VERSION 5.8 ;
BUSBITCHARS "[]" ;
DIVIDERCHAR "/" ;
UNITS
    DATABASE MICRONS 1000 ;
END UNITS

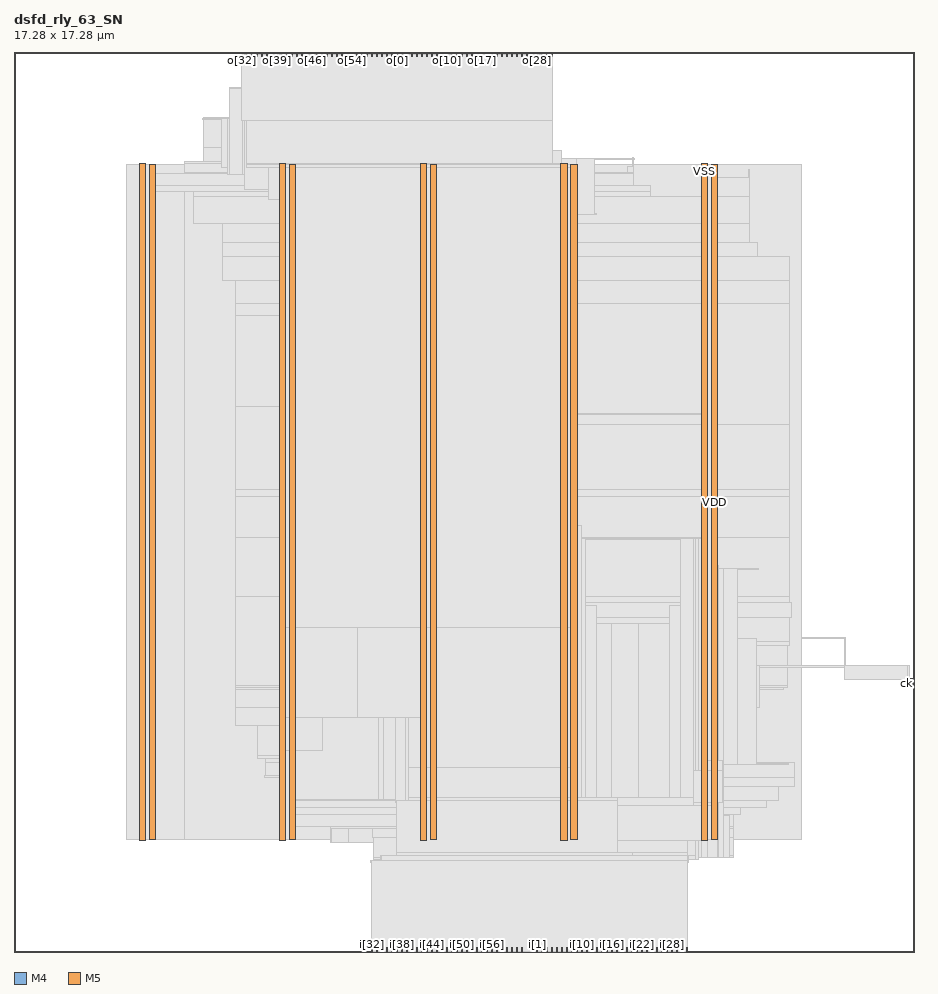
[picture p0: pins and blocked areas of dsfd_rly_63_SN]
MACRO dsfd_rly_63_SN
  FOREIGN dsfd_rly_63_SN 0 0 ;
  CLASS BLOCK ;
  SIZE 17.28 BY 17.28 ;
  PIN ck
    DIRECTION INPUT ;
    USE SIGNAL ;
    PORT
      LAYER M4 ;
        RECT  17.196 5.136 17.28 5.16 ;
    END
  END ck
  PIN i[0]
    DIRECTION INPUT ;
    USE SIGNAL ;
    PORT
      LAYER M5 ;
        RECT  9.936 0 9.96 0.084 ;
    END
  END i[0]
  PIN i[10]
    DIRECTION INPUT ;
    USE SIGNAL ;
    PORT
      LAYER M5 ;
        RECT  10.896 0 10.92 0.084 ;
    END
  END i[10]
  PIN i[11]
    DIRECTION INPUT ;
    USE SIGNAL ;
    PORT
      LAYER M5 ;
        RECT  10.992 0 11.016 0.084 ;
    END
  END i[11]
  PIN i[12]
    DIRECTION INPUT ;
    USE SIGNAL ;
    PORT
      LAYER M5 ;
        RECT  11.088 0 11.112 0.084 ;
    END
  END i[12]
  PIN i[13]
    DIRECTION INPUT ;
    USE SIGNAL ;
    PORT
      LAYER M5 ;
        RECT  11.184 0 11.208 0.084 ;
    END
  END i[13]
  PIN i[14]
    DIRECTION INPUT ;
    USE SIGNAL ;
    PORT
      LAYER M5 ;
        RECT  11.28 0 11.304 0.084 ;
    END
  END i[14]
  PIN i[15]
    DIRECTION INPUT ;
    USE SIGNAL ;
    PORT
      LAYER M5 ;
        RECT  11.376 0 11.4 0.084 ;
    END
  END i[15]
  PIN i[16]
    DIRECTION INPUT ;
    USE SIGNAL ;
    PORT
      LAYER M5 ;
        RECT  11.472 0 11.496 0.084 ;
    END
  END i[16]
  PIN i[17]
    DIRECTION INPUT ;
    USE SIGNAL ;
    PORT
      LAYER M5 ;
        RECT  11.568 0 11.592 0.084 ;
    END
  END i[17]
  PIN i[18]
    DIRECTION INPUT ;
    USE SIGNAL ;
    PORT
      LAYER M5 ;
        RECT  11.664 0 11.688 0.084 ;
    END
  END i[18]
  PIN i[19]
    DIRECTION INPUT ;
    USE SIGNAL ;
    PORT
      LAYER M5 ;
        RECT  11.76 0 11.784 0.084 ;
    END
  END i[19]
  PIN i[1]
    DIRECTION INPUT ;
    USE SIGNAL ;
    PORT
      LAYER M5 ;
        RECT  10.032 0 10.056 0.084 ;
    END
  END i[1]
  PIN i[20]
    DIRECTION INPUT ;
    USE SIGNAL ;
    PORT
      LAYER M5 ;
        RECT  11.856 0 11.88 0.084 ;
    END
  END i[20]
  PIN i[21]
    DIRECTION INPUT ;
    USE SIGNAL ;
    PORT
      LAYER M5 ;
        RECT  11.952 0 11.976 0.084 ;
    END
  END i[21]
  PIN i[22]
    DIRECTION INPUT ;
    USE SIGNAL ;
    PORT
      LAYER M5 ;
        RECT  12.048 0 12.072 0.084 ;
    END
  END i[22]
  PIN i[23]
    DIRECTION INPUT ;
    USE SIGNAL ;
    PORT
      LAYER M5 ;
        RECT  12.144 0 12.168 0.084 ;
    END
  END i[23]
  PIN i[24]
    DIRECTION INPUT ;
    USE SIGNAL ;
    PORT
      LAYER M5 ;
        RECT  12.24 0 12.264 0.084 ;
    END
  END i[24]
  PIN i[25]
    DIRECTION INPUT ;
    USE SIGNAL ;
    PORT
      LAYER M5 ;
        RECT  12.336 0 12.36 0.084 ;
    END
  END i[25]
  PIN i[26]
    DIRECTION INPUT ;
    USE SIGNAL ;
    PORT
      LAYER M5 ;
        RECT  12.432 0 12.456 0.084 ;
    END
  END i[26]
  PIN i[27]
    DIRECTION INPUT ;
    USE SIGNAL ;
    PORT
      LAYER M5 ;
        RECT  12.528 0 12.552 0.084 ;
    END
  END i[27]
  PIN i[28]
    DIRECTION INPUT ;
    USE SIGNAL ;
    PORT
      LAYER M5 ;
        RECT  12.624 0 12.648 0.084 ;
    END
  END i[28]
  PIN i[29]
    DIRECTION INPUT ;
    USE SIGNAL ;
    PORT
      LAYER M5 ;
        RECT  12.72 0 12.744 0.084 ;
    END
  END i[29]
  PIN i[2]
    DIRECTION INPUT ;
    USE SIGNAL ;
    PORT
      LAYER M5 ;
        RECT  10.128 0 10.152 0.084 ;
    END
  END i[2]
  PIN i[30]
    DIRECTION INPUT ;
    USE SIGNAL ;
    PORT
      LAYER M5 ;
        RECT  12.816 0 12.84 0.084 ;
    END
  END i[30]
  PIN i[31]
    DIRECTION INPUT ;
    USE SIGNAL ;
    PORT
      LAYER M5 ;
        RECT  12.912 0 12.936 0.084 ;
    END
  END i[31]
  PIN i[32]
    DIRECTION INPUT ;
    USE SIGNAL ;
    PORT
      LAYER M5 ;
        RECT  6.864 0 6.888 0.084 ;
    END
  END i[32]
  PIN i[33]
    DIRECTION INPUT ;
    USE SIGNAL ;
    PORT
      LAYER M5 ;
        RECT  6.96 0 6.984 0.084 ;
    END
  END i[33]
  PIN i[34]
    DIRECTION INPUT ;
    USE SIGNAL ;
    PORT
      LAYER M5 ;
        RECT  7.056 0 7.08 0.084 ;
    END
  END i[34]
  PIN i[35]
    DIRECTION INPUT ;
    USE SIGNAL ;
    PORT
      LAYER M5 ;
        RECT  7.152 0 7.176 0.084 ;
    END
  END i[35]
  PIN i[36]
    DIRECTION INPUT ;
    USE SIGNAL ;
    PORT
      LAYER M5 ;
        RECT  7.248 0 7.272 0.084 ;
    END
  END i[36]
  PIN i[37]
    DIRECTION INPUT ;
    USE SIGNAL ;
    PORT
      LAYER M5 ;
        RECT  7.344 0 7.368 0.084 ;
    END
  END i[37]
  PIN i[38]
    DIRECTION INPUT ;
    USE SIGNAL ;
    PORT
      LAYER M5 ;
        RECT  7.44 0 7.464 0.084 ;
    END
  END i[38]
  PIN i[39]
    DIRECTION INPUT ;
    USE SIGNAL ;
    PORT
      LAYER M5 ;
        RECT  7.536 0 7.56 0.084 ;
    END
  END i[39]
  PIN i[3]
    DIRECTION INPUT ;
    USE SIGNAL ;
    PORT
      LAYER M5 ;
        RECT  10.224 0 10.248 0.084 ;
    END
  END i[3]
  PIN i[40]
    DIRECTION INPUT ;
    USE SIGNAL ;
    PORT
      LAYER M5 ;
        RECT  7.632 0 7.656 0.084 ;
    END
  END i[40]
  PIN i[41]
    DIRECTION INPUT ;
    USE SIGNAL ;
    PORT
      LAYER M5 ;
        RECT  7.728 0 7.752 0.084 ;
    END
  END i[41]
  PIN i[42]
    DIRECTION INPUT ;
    USE SIGNAL ;
    PORT
      LAYER M5 ;
        RECT  7.824 0 7.848 0.084 ;
    END
  END i[42]
  PIN i[43]
    DIRECTION INPUT ;
    USE SIGNAL ;
    PORT
      LAYER M5 ;
        RECT  7.92 0 7.944 0.084 ;
    END
  END i[43]
  PIN i[44]
    DIRECTION INPUT ;
    USE SIGNAL ;
    PORT
      LAYER M5 ;
        RECT  8.016 0 8.04 0.084 ;
    END
  END i[44]
  PIN i[45]
    DIRECTION INPUT ;
    USE SIGNAL ;
    PORT
      LAYER M5 ;
        RECT  8.112 0 8.136 0.084 ;
    END
  END i[45]
  PIN i[46]
    DIRECTION INPUT ;
    USE SIGNAL ;
    PORT
      LAYER M5 ;
        RECT  8.208 0 8.232 0.084 ;
    END
  END i[46]
  PIN i[47]
    DIRECTION INPUT ;
    USE SIGNAL ;
    PORT
      LAYER M5 ;
        RECT  8.304 0 8.328 0.084 ;
    END
  END i[47]
  PIN i[48]
    DIRECTION INPUT ;
    USE SIGNAL ;
    PORT
      LAYER M5 ;
        RECT  8.4 0 8.424 0.084 ;
    END
  END i[48]
  PIN i[49]
    DIRECTION INPUT ;
    USE SIGNAL ;
    PORT
      LAYER M5 ;
        RECT  8.496 0 8.52 0.084 ;
    END
  END i[49]
  PIN i[4]
    DIRECTION INPUT ;
    USE SIGNAL ;
    PORT
      LAYER M5 ;
        RECT  10.32 0 10.344 0.084 ;
    END
  END i[4]
  PIN i[50]
    DIRECTION INPUT ;
    USE SIGNAL ;
    PORT
      LAYER M5 ;
        RECT  8.592 0 8.616 0.084 ;
    END
  END i[50]
  PIN i[51]
    DIRECTION INPUT ;
    USE SIGNAL ;
    PORT
      LAYER M5 ;
        RECT  8.688 0 8.712 0.084 ;
    END
  END i[51]
  PIN i[52]
    DIRECTION INPUT ;
    USE SIGNAL ;
    PORT
      LAYER M5 ;
        RECT  8.784 0 8.808 0.084 ;
    END
  END i[52]
  PIN i[53]
    DIRECTION INPUT ;
    USE SIGNAL ;
    PORT
      LAYER M5 ;
        RECT  8.88 0 8.904 0.084 ;
    END
  END i[53]
  PIN i[54]
    DIRECTION INPUT ;
    USE SIGNAL ;
    PORT
      LAYER M5 ;
        RECT  8.976 0 9 0.084 ;
    END
  END i[54]
  PIN i[55]
    DIRECTION INPUT ;
    USE SIGNAL ;
    PORT
      LAYER M5 ;
        RECT  9.072 0 9.096 0.084 ;
    END
  END i[55]
  PIN i[56]
    DIRECTION INPUT ;
    USE SIGNAL ;
    PORT
      LAYER M5 ;
        RECT  9.168 0 9.192 0.084 ;
    END
  END i[56]
  PIN i[57]
    DIRECTION INPUT ;
    USE SIGNAL ;
    PORT
      LAYER M5 ;
        RECT  9.264 0 9.288 0.084 ;
    END
  END i[57]
  PIN i[58]
    DIRECTION INPUT ;
    USE SIGNAL ;
    PORT
      LAYER M5 ;
        RECT  9.36 0 9.384 0.084 ;
    END
  END i[58]
  PIN i[59]
    DIRECTION INPUT ;
    USE SIGNAL ;
    PORT
      LAYER M5 ;
        RECT  9.456 0 9.48 0.084 ;
    END
  END i[59]
  PIN i[5]
    DIRECTION INPUT ;
    USE SIGNAL ;
    PORT
      LAYER M5 ;
        RECT  10.416 0 10.44 0.084 ;
    END
  END i[5]
  PIN i[60]
    DIRECTION INPUT ;
    USE SIGNAL ;
    PORT
      LAYER M5 ;
        RECT  9.552 0 9.576 0.084 ;
    END
  END i[60]
  PIN i[61]
    DIRECTION INPUT ;
    USE SIGNAL ;
    PORT
      LAYER M5 ;
        RECT  9.648 0 9.672 0.084 ;
    END
  END i[61]
  PIN i[62]
    DIRECTION INPUT ;
    USE SIGNAL ;
    PORT
      LAYER M5 ;
        RECT  9.744 0 9.768 0.084 ;
    END
  END i[62]
  PIN i[6]
    DIRECTION INPUT ;
    USE SIGNAL ;
    PORT
      LAYER M5 ;
        RECT  10.512 0 10.536 0.084 ;
    END
  END i[6]
  PIN i[7]
    DIRECTION INPUT ;
    USE SIGNAL ;
    PORT
      LAYER M5 ;
        RECT  10.608 0 10.632 0.084 ;
    END
  END i[7]
  PIN i[8]
    DIRECTION INPUT ;
    USE SIGNAL ;
    PORT
      LAYER M5 ;
        RECT  10.704 0 10.728 0.084 ;
    END
  END i[8]
  PIN i[9]
    DIRECTION INPUT ;
    USE SIGNAL ;
    PORT
      LAYER M5 ;
        RECT  10.8 0 10.824 0.084 ;
    END
  END i[9]
  PIN o[0]
    DIRECTION OUTPUT ;
    USE SIGNAL ;
    PORT
      LAYER M5 ;
        RECT  7.344 17.196 7.368 17.28 ;
    END
  END o[0]
  PIN o[10]
    DIRECTION OUTPUT ;
    USE SIGNAL ;
    PORT
      LAYER M5 ;
        RECT  8.304 17.196 8.328 17.28 ;
    END
  END o[10]
  PIN o[11]
    DIRECTION OUTPUT ;
    USE SIGNAL ;
    PORT
      LAYER M5 ;
        RECT  8.4 17.196 8.424 17.28 ;
    END
  END o[11]
  PIN o[12]
    DIRECTION OUTPUT ;
    USE SIGNAL ;
    PORT
      LAYER M5 ;
        RECT  8.496 17.196 8.52 17.28 ;
    END
  END o[12]
  PIN o[13]
    DIRECTION OUTPUT ;
    USE SIGNAL ;
    PORT
      LAYER M5 ;
        RECT  8.592 17.196 8.616 17.28 ;
    END
  END o[13]
  PIN o[14]
    DIRECTION OUTPUT ;
    USE SIGNAL ;
    PORT
      LAYER M5 ;
        RECT  8.688 17.196 8.712 17.28 ;
    END
  END o[14]
  PIN o[15]
    DIRECTION OUTPUT ;
    USE SIGNAL ;
    PORT
      LAYER M5 ;
        RECT  8.784 17.196 8.808 17.28 ;
    END
  END o[15]
  PIN o[16]
    DIRECTION OUTPUT ;
    USE SIGNAL ;
    PORT
      LAYER M5 ;
        RECT  8.88 17.196 8.904 17.28 ;
    END
  END o[16]
  PIN o[17]
    DIRECTION OUTPUT ;
    USE SIGNAL ;
    PORT
      LAYER M5 ;
        RECT  8.976 17.196 9 17.28 ;
    END
  END o[17]
  PIN o[18]
    DIRECTION OUTPUT ;
    USE SIGNAL ;
    PORT
      LAYER M5 ;
        RECT  9.072 17.196 9.096 17.28 ;
    END
  END o[18]
  PIN o[19]
    DIRECTION OUTPUT ;
    USE SIGNAL ;
    PORT
      LAYER M5 ;
        RECT  9.168 17.196 9.192 17.28 ;
    END
  END o[19]
  PIN o[1]
    DIRECTION OUTPUT ;
    USE SIGNAL ;
    PORT
      LAYER M5 ;
        RECT  7.44 17.196 7.464 17.28 ;
    END
  END o[1]
  PIN o[20]
    DIRECTION OUTPUT ;
    USE SIGNAL ;
    PORT
      LAYER M5 ;
        RECT  9.264 17.196 9.288 17.28 ;
    END
  END o[20]
  PIN o[21]
    DIRECTION OUTPUT ;
    USE SIGNAL ;
    PORT
      LAYER M5 ;
        RECT  9.36 17.196 9.384 17.28 ;
    END
  END o[21]
  PIN o[22]
    DIRECTION OUTPUT ;
    USE SIGNAL ;
    PORT
      LAYER M5 ;
        RECT  9.456 17.196 9.48 17.28 ;
    END
  END o[22]
  PIN o[23]
    DIRECTION OUTPUT ;
    USE SIGNAL ;
    PORT
      LAYER M5 ;
        RECT  9.552 17.196 9.576 17.28 ;
    END
  END o[23]
  PIN o[24]
    DIRECTION OUTPUT ;
    USE SIGNAL ;
    PORT
      LAYER M5 ;
        RECT  9.648 17.196 9.672 17.28 ;
    END
  END o[24]
  PIN o[25]
    DIRECTION OUTPUT ;
    USE SIGNAL ;
    PORT
      LAYER M5 ;
        RECT  9.744 17.196 9.768 17.28 ;
    END
  END o[25]
  PIN o[26]
    DIRECTION OUTPUT ;
    USE SIGNAL ;
    PORT
      LAYER M5 ;
        RECT  9.84 17.196 9.864 17.28 ;
    END
  END o[26]
  PIN o[27]
    DIRECTION OUTPUT ;
    USE SIGNAL ;
    PORT
      LAYER M5 ;
        RECT  9.936 17.196 9.96 17.28 ;
    END
  END o[27]
  PIN o[28]
    DIRECTION OUTPUT ;
    USE SIGNAL ;
    PORT
      LAYER M5 ;
        RECT  10.032 17.196 10.056 17.28 ;
    END
  END o[28]
  PIN o[29]
    DIRECTION OUTPUT ;
    USE SIGNAL ;
    PORT
      LAYER M5 ;
        RECT  10.128 17.196 10.152 17.28 ;
    END
  END o[29]
  PIN o[2]
    DIRECTION OUTPUT ;
    USE SIGNAL ;
    PORT
      LAYER M5 ;
        RECT  7.536 17.196 7.56 17.28 ;
    END
  END o[2]
  PIN o[30]
    DIRECTION OUTPUT ;
    USE SIGNAL ;
    PORT
      LAYER M5 ;
        RECT  10.224 17.196 10.248 17.28 ;
    END
  END o[30]
  PIN o[31]
    DIRECTION OUTPUT ;
    USE SIGNAL ;
    PORT
      LAYER M5 ;
        RECT  10.32 17.196 10.344 17.28 ;
    END
  END o[31]
  PIN o[32]
    DIRECTION OUTPUT ;
    USE SIGNAL ;
    PORT
      LAYER M5 ;
        RECT  4.368 17.196 4.392 17.28 ;
    END
  END o[32]
  PIN o[33]
    DIRECTION OUTPUT ;
    USE SIGNAL ;
    PORT
      LAYER M5 ;
        RECT  4.464 17.196 4.488 17.28 ;
    END
  END o[33]
  PIN o[34]
    DIRECTION OUTPUT ;
    USE SIGNAL ;
    PORT
      LAYER M5 ;
        RECT  4.56 17.196 4.584 17.28 ;
    END
  END o[34]
  PIN o[35]
    DIRECTION OUTPUT ;
    USE SIGNAL ;
    PORT
      LAYER M5 ;
        RECT  4.656 17.196 4.68 17.28 ;
    END
  END o[35]
  PIN o[36]
    DIRECTION OUTPUT ;
    USE SIGNAL ;
    PORT
      LAYER M5 ;
        RECT  4.752 17.196 4.776 17.28 ;
    END
  END o[36]
  PIN o[37]
    DIRECTION OUTPUT ;
    USE SIGNAL ;
    PORT
      LAYER M5 ;
        RECT  4.848 17.196 4.872 17.28 ;
    END
  END o[37]
  PIN o[38]
    DIRECTION OUTPUT ;
    USE SIGNAL ;
    PORT
      LAYER M5 ;
        RECT  4.944 17.196 4.968 17.28 ;
    END
  END o[38]
  PIN o[39]
    DIRECTION OUTPUT ;
    USE SIGNAL ;
    PORT
      LAYER M5 ;
        RECT  5.04 17.196 5.064 17.28 ;
    END
  END o[39]
  PIN o[3]
    DIRECTION OUTPUT ;
    USE SIGNAL ;
    PORT
      LAYER M5 ;
        RECT  7.632 17.196 7.656 17.28 ;
    END
  END o[3]
  PIN o[40]
    DIRECTION OUTPUT ;
    USE SIGNAL ;
    PORT
      LAYER M5 ;
        RECT  5.136 17.196 5.16 17.28 ;
    END
  END o[40]
  PIN o[41]
    DIRECTION OUTPUT ;
    USE SIGNAL ;
    PORT
      LAYER M5 ;
        RECT  5.232 17.196 5.256 17.28 ;
    END
  END o[41]
  PIN o[42]
    DIRECTION OUTPUT ;
    USE SIGNAL ;
    PORT
      LAYER M5 ;
        RECT  5.328 17.196 5.352 17.28 ;
    END
  END o[42]
  PIN o[43]
    DIRECTION OUTPUT ;
    USE SIGNAL ;
    PORT
      LAYER M5 ;
        RECT  5.424 17.196 5.448 17.28 ;
    END
  END o[43]
  PIN o[44]
    DIRECTION OUTPUT ;
    USE SIGNAL ;
    PORT
      LAYER M5 ;
        RECT  5.52 17.196 5.544 17.28 ;
    END
  END o[44]
  PIN o[45]
    DIRECTION OUTPUT ;
    USE SIGNAL ;
    PORT
      LAYER M5 ;
        RECT  5.616 17.196 5.64 17.28 ;
    END
  END o[45]
  PIN o[46]
    DIRECTION OUTPUT ;
    USE SIGNAL ;
    PORT
      LAYER M5 ;
        RECT  5.712 17.196 5.736 17.28 ;
    END
  END o[46]
  PIN o[47]
    DIRECTION OUTPUT ;
    USE SIGNAL ;
    PORT
      LAYER M5 ;
        RECT  5.808 17.196 5.832 17.28 ;
    END
  END o[47]
  PIN o[48]
    DIRECTION OUTPUT ;
    USE SIGNAL ;
    PORT
      LAYER M5 ;
        RECT  5.904 17.196 5.928 17.28 ;
    END
  END o[48]
  PIN o[49]
    DIRECTION OUTPUT ;
    USE SIGNAL ;
    PORT
      LAYER M5 ;
        RECT  6 17.196 6.024 17.28 ;
    END
  END o[49]
  PIN o[4]
    DIRECTION OUTPUT ;
    USE SIGNAL ;
    PORT
      LAYER M5 ;
        RECT  7.728 17.196 7.752 17.28 ;
    END
  END o[4]
  PIN o[50]
    DIRECTION OUTPUT ;
    USE SIGNAL ;
    PORT
      LAYER M5 ;
        RECT  6.096 17.196 6.12 17.28 ;
    END
  END o[50]
  PIN o[51]
    DIRECTION OUTPUT ;
    USE SIGNAL ;
    PORT
      LAYER M5 ;
        RECT  6.192 17.196 6.216 17.28 ;
    END
  END o[51]
  PIN o[52]
    DIRECTION OUTPUT ;
    USE SIGNAL ;
    PORT
      LAYER M5 ;
        RECT  6.288 17.196 6.312 17.28 ;
    END
  END o[52]
  PIN o[53]
    DIRECTION OUTPUT ;
    USE SIGNAL ;
    PORT
      LAYER M5 ;
        RECT  6.384 17.196 6.408 17.28 ;
    END
  END o[53]
  PIN o[54]
    DIRECTION OUTPUT ;
    USE SIGNAL ;
    PORT
      LAYER M5 ;
        RECT  6.48 17.196 6.504 17.28 ;
    END
  END o[54]
  PIN o[55]
    DIRECTION OUTPUT ;
    USE SIGNAL ;
    PORT
      LAYER M5 ;
        RECT  6.576 17.196 6.6 17.28 ;
    END
  END o[55]
  PIN o[56]
    DIRECTION OUTPUT ;
    USE SIGNAL ;
    PORT
      LAYER M5 ;
        RECT  6.672 17.196 6.696 17.28 ;
    END
  END o[56]
  PIN o[57]
    DIRECTION OUTPUT ;
    USE SIGNAL ;
    PORT
      LAYER M5 ;
        RECT  6.768 17.196 6.792 17.28 ;
    END
  END o[57]
  PIN o[58]
    DIRECTION OUTPUT ;
    USE SIGNAL ;
    PORT
      LAYER M5 ;
        RECT  6.864 17.196 6.888 17.28 ;
    END
  END o[58]
  PIN o[59]
    DIRECTION OUTPUT ;
    USE SIGNAL ;
    PORT
      LAYER M5 ;
        RECT  6.96 17.196 6.984 17.28 ;
    END
  END o[59]
  PIN o[5]
    DIRECTION OUTPUT ;
    USE SIGNAL ;
    PORT
      LAYER M5 ;
        RECT  7.824 17.196 7.848 17.28 ;
    END
  END o[5]
  PIN o[60]
    DIRECTION OUTPUT ;
    USE SIGNAL ;
    PORT
      LAYER M5 ;
        RECT  7.056 17.196 7.08 17.28 ;
    END
  END o[60]
  PIN o[61]
    DIRECTION OUTPUT ;
    USE SIGNAL ;
    PORT
      LAYER M5 ;
        RECT  7.152 17.196 7.176 17.28 ;
    END
  END o[61]
  PIN o[62]
    DIRECTION OUTPUT ;
    USE SIGNAL ;
    PORT
      LAYER M5 ;
        RECT  7.248 17.196 7.272 17.28 ;
    END
  END o[62]
  PIN o[6]
    DIRECTION OUTPUT ;
    USE SIGNAL ;
    PORT
      LAYER M5 ;
        RECT  7.92 17.196 7.944 17.28 ;
    END
  END o[6]
  PIN o[7]
    DIRECTION OUTPUT ;
    USE SIGNAL ;
    PORT
      LAYER M5 ;
        RECT  8.016 17.196 8.04 17.28 ;
    END
  END o[7]
  PIN o[8]
    DIRECTION OUTPUT ;
    USE SIGNAL ;
    PORT
      LAYER M5 ;
        RECT  8.112 17.196 8.136 17.28 ;
    END
  END o[8]
  PIN o[9]
    DIRECTION OUTPUT ;
    USE SIGNAL ;
    PORT
      LAYER M5 ;
        RECT  8.208 17.196 8.232 17.28 ;
    END
  END o[9]
  PIN rs
    DIRECTION INPUT ;
    USE SIGNAL ;
    PORT
      LAYER M4 ;
        RECT  17.196 5.232 17.28 5.256 ;
    END
  END rs
  PIN VDD
    DIRECTION INOUT ;
    USE POWER ;
    PORT
      LAYER M5 ;
        RECT  13.392 2.151 13.512 15.129 ;
        RECT  10.692 2.151 10.812 15.129 ;
        RECT  7.992 2.151 8.112 15.129 ;
        RECT  5.292 2.151 5.412 15.129 ;
        RECT  2.592 2.151 2.712 15.129 ;
    END
  END VDD
  PIN VSS
    DIRECTION INOUT ;
    USE GROUND ;
    PORT
      LAYER M5 ;
        RECT  13.2 2.137 13.32 15.143 ;
        RECT  10.5 2.137 10.62 15.143 ;
        RECT  7.8 2.137 7.92 15.143 ;
        RECT  5.1 2.137 5.22 15.143 ;
        RECT  2.4 2.137 2.52 15.143 ;
    END
  END VSS
  # OT_OBS_CLOSED layer=M5 d_um=1.536 added=6
  OBS
    LAYER RVTN ;
     RECT  2.16 2.16 15.12 2.295 ;
     RECT  2.16 2.565 15.12 2.835 ;
     RECT  2.16 3.105 15.12 3.375 ;
     RECT  2.16 3.645 15.12 3.915 ;
     RECT  2.16 4.185 15.12 4.455 ;
     RECT  2.16 4.725 15.12 4.995 ;
     RECT  2.16 5.265 15.12 5.535 ;
     RECT  2.16 5.805 15.12 6.075 ;
     RECT  2.16 6.345 15.12 6.615 ;
     RECT  2.16 6.885 15.12 7.155 ;
     RECT  2.16 7.425 15.12 7.695 ;
     RECT  2.16 7.965 15.12 8.235 ;
     RECT  2.16 8.505 15.12 8.775 ;
     RECT  2.16 9.045 15.12 9.315 ;
     RECT  2.16 9.585 15.12 9.855 ;
     RECT  2.16 10.125 15.12 10.395 ;
     RECT  2.16 10.665 15.12 10.935 ;
     RECT  2.16 11.205 15.12 11.475 ;
     RECT  2.16 11.745 15.12 12.015 ;
     RECT  2.16 12.285 15.12 12.555 ;
     RECT  2.16 12.825 15.12 13.095 ;
     RECT  2.16 13.365 15.12 13.635 ;
     RECT  2.16 13.905 15.12 14.175 ;
     RECT  2.16 14.445 15.12 14.715 ;
     RECT  2.16 14.985 15.12 15.12 ;
    LAYER RVTP ;
     RECT  2.16 2.295 15.12 2.565 ;
     RECT  2.16 2.835 15.12 3.105 ;
     RECT  2.16 3.375 15.12 3.645 ;
     RECT  2.16 3.915 15.12 4.185 ;
     RECT  2.16 4.455 15.12 4.725 ;
     RECT  2.16 4.995 15.12 5.265 ;
     RECT  2.16 5.535 15.12 5.805 ;
     RECT  2.16 6.075 15.12 6.345 ;
     RECT  2.16 6.615 15.12 6.885 ;
     RECT  2.16 7.155 15.12 7.425 ;
     RECT  2.16 7.695 15.12 7.965 ;
     RECT  2.16 8.235 15.12 8.505 ;
     RECT  2.16 8.775 15.12 9.045 ;
     RECT  2.16 9.315 15.12 9.585 ;
     RECT  2.16 9.855 15.12 10.125 ;
     RECT  2.16 10.395 15.12 10.665 ;
     RECT  2.16 10.935 15.12 11.205 ;
     RECT  2.16 11.475 15.12 11.745 ;
     RECT  2.16 12.015 15.12 12.285 ;
     RECT  2.16 12.555 15.12 12.825 ;
     RECT  2.16 13.095 15.12 13.365 ;
     RECT  2.16 13.635 15.12 13.905 ;
     RECT  2.16 14.175 15.12 14.445 ;
     RECT  2.16 14.715 15.12 14.985 ;
    LAYER M1 ;
     RECT  2.16 2.151 15.12 15.129 ;
    LAYER M2 ;
     RECT  2.16 2.151 3.271 15.129 ;
     RECT  3.271 2.151 6.079 15.174 ;
     RECT  6.079 2.106 6.431 15.174 ;
     RECT  6.431 2.106 9.239 15.129 ;
     RECT  10.939 1.152 11.039 1.17 ;
     RECT  9.239 2.151 15.12 15.129 ;
     RECT  15.12 6.012 15.971 6.03 ;
    LAYER M3 ;
     RECT  10.908 0.091 10.926 0.139 ;
     RECT  6.912 0.571 6.93 0.619 ;
     RECT  6.912 0.619 7.002 1.723 ;
     RECT  9.072 1.099 9.09 1.723 ;
     RECT  10.908 0.139 11.034 1.723 ;
     RECT  12.6 1.147 12.618 1.723 ;
     RECT  6.912 1.723 10.17 1.771 ;
     RECT  10.908 1.723 12.942 1.771 ;
     RECT  6.912 1.771 13.122 1.819 ;
     RECT  6.912 1.819 13.806 2.191 ;
     RECT  6.084 2.101 6.102 2.371 ;
     RECT  6.876 2.191 13.806 2.371 ;
     RECT  2.415 2.143 2.505 2.413 ;
     RECT  5.115 2.143 5.205 2.413 ;
     RECT  6.084 2.371 13.806 2.413 ;
     RECT  5.115 2.413 13.806 2.641 ;
     RECT  5.115 2.641 13.95 2.767 ;
     RECT  5.115 2.767 14.454 2.911 ;
     RECT  5.115 2.911 14.67 3.181 ;
     RECT  5.115 3.181 14.994 3.343 ;
     RECT  4.824 3.343 14.994 3.629 ;
     RECT  14.976 3.629 14.994 3.641 ;
     RECT  4.824 3.629 14.238 3.721 ;
     RECT  4.68 3.721 14.238 3.773 ;
     RECT  4.68 3.773 14.202 4.351 ;
     RECT  4.248 4.351 14.202 4.699 ;
     RECT  4.248 4.699 14.31 5.035 ;
     RECT  4.248 5.035 14.778 5.071 ;
     RECT  4.248 5.071 14.85 5.117 ;
     RECT  17.172 5.131 17.19 5.501 ;
     RECT  6.408 5.117 14.85 5.881 ;
     RECT  6.408 5.881 14.886 5.971 ;
     RECT  15.948 5.227 15.966 6.035 ;
     RECT  6.336 5.971 14.886 6.421 ;
     RECT  6.336 6.421 14.922 6.719 ;
     RECT  4.248 5.117 5.598 6.817 ;
     RECT  6.336 6.719 14.886 6.817 ;
     RECT  4.248 6.817 14.886 7.949 ;
     RECT  4.248 7.949 8.097 8.743 ;
     RECT  8.82 7.949 14.886 8.743 ;
     RECT  4.248 8.743 14.886 8.879 ;
     RECT  10.224 8.879 14.886 10.121 ;
     RECT  4.248 8.879 9.414 10.471 ;
     RECT  4.248 10.471 9.702 12.217 ;
     RECT  4.248 12.217 9.774 12.451 ;
     RECT  10.515 10.121 14.886 12.451 ;
     RECT  4.248 12.451 14.886 12.901 ;
     RECT  3.996 12.901 14.886 13.361 ;
     RECT  3.996 13.361 14.274 13.631 ;
     RECT  3.996 13.631 14.13 13.981 ;
     RECT  3.456 13.981 14.13 14.513 ;
     RECT  2.415 2.413 2.697 14.611 ;
     RECT  3.456 14.513 12.222 14.611 ;
     RECT  2.415 14.611 12.222 14.711 ;
     RECT  13.215 14.513 14.13 14.867 ;
     RECT  2.415 14.711 11.898 14.945 ;
     RECT  3.276 14.945 11.898 14.957 ;
     RECT  14.112 14.867 14.13 15.017 ;
     RECT  11.772 14.957 11.898 15.089 ;
     RECT  2.415 14.945 2.505 15.137 ;
     RECT  3.276 14.957 10.605 15.137 ;
     RECT  13.215 14.867 13.305 15.137 ;
     RECT  3.276 15.137 7.542 15.179 ;
     RECT  11.88 15.089 11.898 15.245 ;
     RECT  8.388 15.137 10.494 15.389 ;
     RECT  3.636 15.179 7.542 15.437 ;
     RECT  3.636 15.437 6.822 16.013 ;
     RECT  8.388 15.389 8.406 16.013 ;
     RECT  4.14 16.013 6.822 16.061 ;
     RECT  4.14 16.061 4.878 16.109 ;
     RECT  5.652 16.061 6.822 16.493 ;
     RECT  5.652 16.493 6.714 16.541 ;
     RECT  4.14 16.109 4.518 16.589 ;
     RECT  4.392 16.589 4.518 16.637 ;
     RECT  4.392 16.637 4.41 16.685 ;
     RECT  5.724 16.541 6.174 17.165 ;
    LAYER M4 ;
     RECT  2.408 2.148 2.512 15.132 ;
     RECT  2.512 2.418 2.704 14.862 ;
     RECT  3.625 15.984 3.985 16.008 ;
     RECT  3.985 15.072 4.093 16.008 ;
     RECT  4.093 14.928 4.129 16.008 ;
     RECT  4.129 14.928 4.381 16.584 ;
     RECT  4.381 14.928 4.417 16.68 ;
     RECT  4.417 14.64 4.885 16.68 ;
     RECT  4.813 3.36 5.108 3.384 ;
     RECT  4.885 14.448 5.108 16.68 ;
     RECT  5.108 2.148 5.212 16.68 ;
     RECT  5.212 2.418 5.404 16.68 ;
     RECT  5.404 13.056 5.555 16.68 ;
     RECT  5.555 16.512 5.669 16.68 ;
     RECT  5.555 13.056 5.843 15.432 ;
     RECT  5.669 16.512 6.185 17.16 ;
     RECT  5.843 13.68 6.293 15.432 ;
     RECT  6.185 16.512 6.544 17.064 ;
     RECT  5.404 11.376 6.709 12.024 ;
     RECT  6.544 16.464 6.709 17.064 ;
     RECT  6.709 11.328 6.805 12.024 ;
     RECT  6.709 16.416 6.853 17.064 ;
     RECT  6.901 0.576 6.973 0.6 ;
     RECT  6.853 16.32 6.995 17.064 ;
     RECT  5.404 2.928 6.997 5.928 ;
     RECT  6.853 1.728 7.037 1.752 ;
     RECT  6.997 2.928 7.093 6.264 ;
     RECT  6.757 7.392 7.093 7.416 ;
     RECT  6.805 10.848 7.093 12.024 ;
     RECT  6.973 0.576 7.283 0.648 ;
     RECT  7.093 2.928 7.333 7.416 ;
     RECT  7.093 10.848 7.381 12.552 ;
     RECT  6.293 13.68 7.484 14.952 ;
     RECT  7.333 2.88 7.525 7.416 ;
     RECT  6.995 16.992 7.573 17.064 ;
     RECT  7.037 1.728 7.621 1.848 ;
     RECT  7.525 2.88 7.621 7.944 ;
     RECT  7.573 0.192 7.669 0.216 ;
     RECT  7.621 1.728 7.808 7.944 ;
     RECT  7.381 10.848 7.808 12.6 ;
     RECT  7.484 13.68 7.808 15.432 ;
     RECT  7.669 0.144 7.859 0.216 ;
     RECT  7.573 16.992 7.859 17.112 ;
     RECT  7.859 0.192 7.955 0.216 ;
     RECT  7.808 1.728 8.104 15.432 ;
     RECT  8.104 1.728 8.165 1.8 ;
     RECT  8.104 2.832 8.165 7.944 ;
     RECT  8.104 11.232 8.237 14.28 ;
     RECT  7.859 17.04 8.291 17.112 ;
     RECT  8.104 15.36 8.377 15.432 ;
     RECT  8.291 17.088 8.387 17.112 ;
     RECT  8.377 15.36 8.627 16.008 ;
     RECT  8.237 11.376 8.777 14.28 ;
     RECT  8.165 1.728 9.061 1.752 ;
     RECT  8.777 11.856 9.137 14.28 ;
     RECT  8.165 2.832 9.205 7.464 ;
     RECT  9.137 12.288 9.281 14.28 ;
     RECT  9.061 1.104 9.324 1.752 ;
     RECT  8.627 15.36 9.424 15.384 ;
     RECT  9.324 1.104 9.491 1.8 ;
     RECT  9.205 2.832 9.637 7.656 ;
     RECT  9.281 12.384 9.637 14.28 ;
     RECT  9.424 15.312 9.637 15.384 ;
     RECT  9.491 1.728 10.105 1.8 ;
     RECT  9.637 2.832 10.105 8.184 ;
     RECT  9.637 12.384 10.505 15.384 ;
     RECT  10.105 1.728 10.508 8.184 ;
     RECT  9.877 10.32 10.508 10.344 ;
     RECT  10.505 12.384 10.508 15.24 ;
     RECT  10.261 0.144 10.547 0.264 ;
     RECT  10.508 1.728 10.804 15.24 ;
     RECT  10.547 0.144 10.853 0.168 ;
     RECT  10.804 1.728 10.901 8.184 ;
     RECT  10.853 0.096 10.937 0.168 ;
     RECT  10.901 1.728 10.973 7.944 ;
     RECT  10.937 0.144 11.045 0.168 ;
     RECT  10.804 14.16 11.153 15.24 ;
     RECT  10.973 1.728 11.189 6.648 ;
     RECT  11.153 14.16 11.189 14.184 ;
     RECT  11.189 1.728 11.477 6.312 ;
     RECT  11.477 1.728 11.891 1.896 ;
     RECT  11.153 15.216 11.909 15.24 ;
     RECT  11.477 2.88 11.981 6.312 ;
     RECT  11.891 1.728 12.589 1.848 ;
     RECT  11.981 2.928 12.589 6.312 ;
     RECT  12.589 1.152 12.673 1.848 ;
     RECT  12.589 2.928 12.805 6.648 ;
     RECT  10.973 7.92 12.805 7.944 ;
     RECT  12.673 1.728 12.953 1.848 ;
     RECT  12.805 2.928 13.045 7.944 ;
     RECT  12.953 1.776 13.093 1.848 ;
     RECT  13.045 2.832 13.093 7.944 ;
     RECT  13.093 1.776 13.133 7.944 ;
     RECT  13.133 1.824 13.208 7.944 ;
     RECT  10.804 10.32 13.208 10.344 ;
     RECT  13.208 1.824 13.312 15.132 ;
     RECT  13.312 1.824 13.504 14.862 ;
     RECT  13.504 1.824 13.529 7.416 ;
     RECT  13.529 1.824 13.619 7.368 ;
     RECT  13.619 1.824 13.745 2.616 ;
     RECT  13.745 1.824 13.817 1.848 ;
     RECT  13.619 3.6 13.889 7.368 ;
     RECT  13.889 3.6 14.249 6.024 ;
     RECT  13.889 7.344 14.285 7.368 ;
     RECT  14.249 4.704 14.321 5.496 ;
     RECT  14.249 3.6 14.861 3.624 ;
     RECT  14.321 5.472 15.937 5.496 ;
     RECT  15.937 5.232 17.161 5.496 ;
     RECT  17.161 5.136 17.201 5.496 ;
     RECT  17.201 5.136 17.244 5.256 ;
    LAYER M5 ;
     RECT  6.864 0.016 12.936 1.763 ;
     RECT  7.056 1.763 12.936 1.859 ;
     RECT  7.344 1.859 11.88 1.907 ;
     RECT  2.4 2.137 2.52 2.151 ;
     RECT  5.1 2.137 5.22 2.151 ;
     RECT  13.2 2.137 13.32 2.151 ;
     RECT  13.2 2.151 13.512 2.821 ;
     RECT  13.056 2.821 13.512 2.869 ;
     RECT  7.344 1.907 11.592 2.915 ;
     RECT  7.584 2.915 11.592 2.963 ;
     RECT  13.056 2.869 13.608 3.491 ;
     RECT  7.584 2.963 10.812 3.539 ;
     RECT  13.2 3.491 13.608 3.683 ;
     RECT  5.1 2.151 5.412 3.877 ;
     RECT  5.1 3.877 5.928 4.501 ;
     RECT  5.1 4.501 6.6 6.229 ;
     RECT  7.8 3.539 10.812 6.229 ;
     RECT  5.1 6.229 10.812 15.061 ;
     RECT  2.4 2.151 2.712 15.129 ;
     RECT  4.464 15.061 10.812 15.129 ;
     RECT  13.2 3.683 13.512 15.129 ;
     RECT  2.4 15.129 2.52 15.143 ;
     RECT  4.464 15.129 10.62 15.143 ;
     RECT  13.2 15.129 13.32 15.143 ;
     RECT  4.464 15.143 10.344 15.973 ;
     RECT  4.368 15.973 10.344 17.232 ;
     RECT  11.88 1.859 12.936 1.907 ;
     RECT  11.592 1.907 12.936 2.137 ;
     RECT  11.592 2.137 13.2 2.821 ;
     RECT  11.592 2.821 13.056 2.963 ;
     RECT  7.584 3.539 7.8 4.501 ;
     RECT  6.6 4.501 7.8 6.229 ;
  END
END dsfd_rly_63_SN
END LIBRARY
